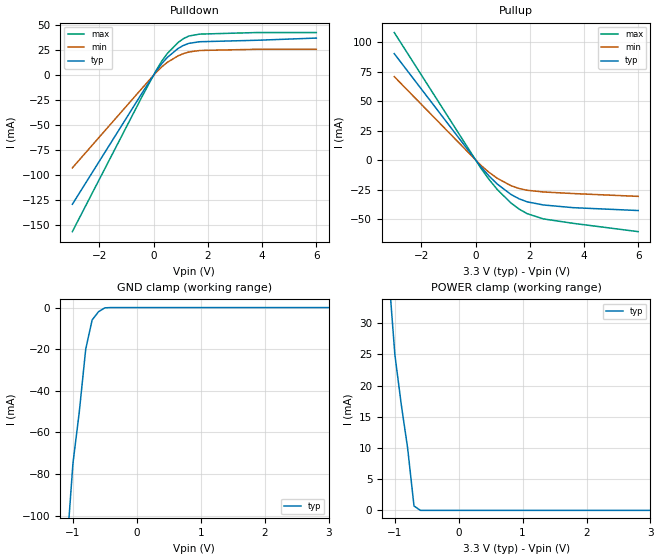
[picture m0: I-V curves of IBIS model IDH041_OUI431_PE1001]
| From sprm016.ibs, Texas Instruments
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[Model]   IDH041_OUI431_PE1001
Model_type   I/O
Polarity   Non-Inverting
Enable   Active-Low
| signals   A,GZ, Y
Vinl = 0.8V
Vinh = 2.0V
Cref = 30p
Rref = 50
Vref = 1.5
Vmeas = 1.5
|   typ   min   max
C_comp   6.0116p   5.8732p   6.5695p
|   typ   min   max
[Temperature Range]   25.0   0   90
|   typ   min   max
[Voltage Range]   3.3V   3.13V   3.47V
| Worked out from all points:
|   slope of the pulldown table from 0 to 0.495 V, typ, clamps not added: 28.2 ohm
|   slope of the pullup table from 0 to 0.495 V, typ, clamps not added: 36.9 ohm
|   GND clamp passes 1 mA (typ) near -0.55 V on its own axis
|   POWER clamp passes 1 mA (typ) near -0.70 V on its own axis
[Pulldown]
|   Voltage   I(typ)   I(min)   I(max)
-3V       -129.3mA   -92.87mA   -156.7mA
-400mV    -16.7mA    -12.27mA   -19.97mA
100mV     4.193mA    2.994mA    5.105mA
300mV     11.56mA    8.294mA    14.08mA
500mV     17.69mA    12.74mA    21.57mA
900mV     26.69mA    19.31mA    32.68mA
1.1V      29.74mA    21.56mA    36.53mA
1.3V      31.83mA    23.17mA    39.17mA
1.7V      33.43mA    24.68mA    41.07mA
3.8V      34.9mA     25.88mA    42.64mA
6V        37.1mA     25.88mA    42.64mA
[GND_clamp]
|   Voltage   I(typ)   I(min)   I(max)
-3V       -900mA     NA         NA
-2V       -500mA     NA         NA
-1V       -75mA      NA         NA
-900mV    -50mA      NA         NA
-800mV    -20mA      NA         NA
-700mV    -6mA       NA         NA
-600mV    -2mA       NA         NA
-500mV    -120uA     NA         NA
-400mV    0A         NA         NA
3V        0A         NA         NA
[Pullup]
|   Voltage   I(typ)   I(min)   I(max)
-3V       90.12mA    70.68mA    108mA
200mV     -5.759mA   -4.466mA   -6.95mA
500mV     -13.53mA   -10.39mA   -16.46mA
800mV     -20.23mA   -15.37mA   -24.83mA
1.3V      -28.96mA   -21.55mA   -36.18mA
1.6V      -32.7mA    -23.98mA   -41.36mA
1.9V      -35.28mA   -25.48mA   -45.27mA
2.5V      -37.94mA   -26.94mA   -49.74mA
3.6V      -40.23mA   -28.28mA   -53.49mA
6V        -42.65mA   -30.68mA   -60.52mA
[POWER_clamp]
|   Voltage   I(typ)   I(min)   I(max)
-3V       300mA      NA         NA
-2V       160mA      NA         NA
-1V       25mA       NA         NA
-900mV    17mA       NA         NA
-800mV    10mA       NA         NA
-700mV    700uA      NA         NA
-600mV    0A         NA         NA
-500mV    0A         NA         NA
3V        0A         NA         NA
[Ramp]
|   I(typ)   I(min)   I(max)
dV/dt_r   0.999/0.120n   0.749/0.140n   1.198/0.100n
dV/dt_f   0.994/0.160n   0.760/0.220n   1.179/0.130n
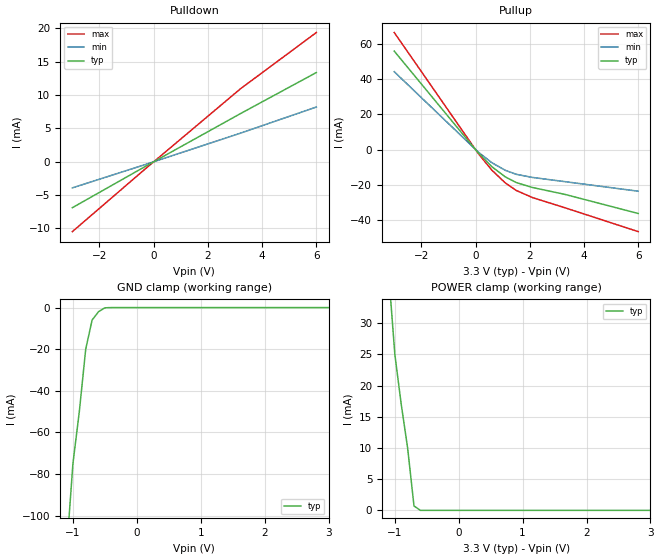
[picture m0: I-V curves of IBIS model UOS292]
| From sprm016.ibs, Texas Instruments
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[Model]   UOS292
Model_type   Output
Polarity   Non-Inverting
Enable   Active-Low
| signals   ZSETSTATUS, PCLRPMEST, ALLOW, PDPMEEN, PCLKPMEEN,
|   DCLRPMEEN, PMEST, PMEEN, PME
Cref = 30p
Rref = 50
Vref = 1.5
Vmeas = 1.5
|   typ   min   max
C_comp   0p   0p   0p
|   typ   min   max
[Temperature Range]   25.0   0   90
|   typ   min   max
[Voltage Range]   3.3V   3.13V   3.47V
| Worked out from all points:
|   slope of the pulldown table from 0 to 0.495 V, typ, clamps not added: 441 ohm
|   slope of the pullup table from 0 to 0.495 V, typ, clamps not added: 60.8 ohm
|   GND clamp passes 1 mA (typ) near -0.55 V on its own axis
|   POWER clamp passes 1 mA (typ) near -0.70 V on its own axis
[Pulldown]
|   Voltage   I(typ)   I(min)   I(max)
-3V       -6.89mA    -3.916mA   -10.48mA
-300mV    -681uA     -404uA     -1.036mA
3.2V      7.22mA     4.287mA    10.94mA
6V        13.38mA    8.207mA    19.38mA
[GND_clamp]
|   Voltage   I(typ)   I(min)   I(max)
-3V       -900mA     NA         NA
-2V       -500mA     NA         NA
-1V       -75mA      NA         NA
-900mV    -50mA      NA         NA
-800mV    -20mA      NA         NA
-700mV    -6mA       NA         NA
-600mV    -2mA       NA         NA
-500mV    -120uA     NA         NA
-400mV    0A         NA         NA
3V        0A         NA         NA
[Pullup]
|   Voltage   I(typ)   I(min)   I(max)
-3V       55.81mA    44.17mA    66.34mA
100mV     -1.837mA   -1.343mA   -2.177mA
600mV     -9.619mA   -7.365mA   -11.59mA
1.1V      -15.42mA   -11.69mA   -18.85mA
1.5V      -18.59mA   -13.92mA   -23.05mA
2.1V      -21.39mA   -15.7mA    -27.1mA
3.3V      -25.31mA   -18.09mA   -32.88mA
6V        -36.11mA   -23.49mA   -46.38mA
[POWER_clamp]
|   Voltage   I(typ)   I(min)   I(max)
-3V       300mA      NA         NA
-2V       160mA      NA         NA
-1V       25mA       NA         NA
-900mV    17mA       NA         NA
-800mV    10mA       NA         NA
-700mV    700uA      NA         NA
-600mV    0A         NA         NA
-500mV    0A         NA         NA
3V        0A         NA         NA
[Ramp]
|   I(typ)   I(min)   I(max)
dV/dt_r   1.754/0.320n   1.713/0.360n   1.783/0.310n
dV/dt_f   1.753/1.070n   1.703/1.720n   1.783/0.740n
